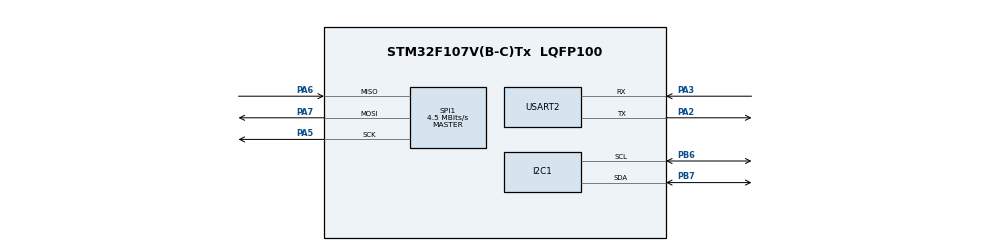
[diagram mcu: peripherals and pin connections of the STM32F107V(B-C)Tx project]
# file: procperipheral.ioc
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Dma.Request0=USART2_TX
Dma.USART2_TX.0.Direction=DMA_MEMORY_TO_PERIPH
Dma.USART2_TX.0.Instance=DMA1_Channel7
Dma.USART2_TX.0.MemDataAlignment=DMA_MDATAALIGN_BYTE
Dma.USART2_TX.0.MemInc=DMA_MINC_ENABLE
Dma.USART2_TX.0.Mode=DMA_NORMAL
Dma.USART2_TX.0.PeriphDataAlignment=DMA_PDATAALIGN_BYTE
Dma.USART2_TX.0.PeriphInc=DMA_PINC_DISABLE
Dma.USART2_TX.0.Priority=DMA_PRIORITY_LOW
Mcu.Family=STM32F1
Mcu.Name=STM32F107V(B-C)Tx
Mcu.Package=LQFP100
NVIC.DMA1_Channel7_IRQn=true\:0\:0\:false\:false\:true\:false\:true\:true
NVIC.PriorityGroup=NVIC_PRIORITYGROUP_4
NVIC.USART2_IRQn=true\:0\:0\:false\:false\:true\:true\:true\:true
OSC_IN.Mode=HSE-External-Oscillator
OSC_IN.Signal=RCC_OSC_IN
OSC_OUT.Mode=HSE-External-Oscillator
OSC_OUT.Signal=RCC_OSC_OUT
PA13.Mode=Serial_Wire
PA13.Signal=SYS_JTMS-SWDIO
PA14.Mode=Serial_Wire
PA14.Signal=SYS_JTCK-SWCLK
PA2.Mode=Asynchronous
PA2.Signal=USART2_TX
PA3.Mode=Asynchronous
PA3.Signal=USART2_RX
PA5.Mode=Full_Duplex_Master
PA5.Signal=SPI1_SCK
PA6.Mode=Full_Duplex_Master
PA6.Signal=SPI1_MISO
PA7.Mode=Full_Duplex_Master
PA7.Signal=SPI1_MOSI
PB6.Mode=I2C
PB6.Signal=I2C1_SCL
PB7.Mode=I2C
PB7.Signal=I2C1_SDA
PC14-OSC32_IN.Mode=LSE-External-Oscillator
PC14-OSC32_IN.Signal=RCC_OSC32_IN
PC15-OSC32_OUT.Mode=LSE-External-Oscillator
PC15-OSC32_OUT.Signal=RCC_OSC32_OUT
ProjectManager.HeapSize=0x200
ProjectManager.StackSize=0x400
ProjectManager.TargetToolchain=STM32CubeIDE
RCC.AHBFreq_Value=72000000
RCC.APB1CLKDivider=RCC_HCLK_DIV2
RCC.APB1Freq_Value=36000000
RCC.APB1TimFreq_Value=72000000
RCC.APB2Freq_Value=72000000
RCC.APB2TimFreq_Value=72000000
RCC.EnbaleCSS=true
RCC.HCLKFreq_Value=72000000
RCC.HSEDivPLL=RCC_HSE_PREDIV_DIV5
RCC.HSE_VALUE=25000000
RCC.PLLMUL=RCC_PLL_MUL9
RCC.PLLSourceVirtual=RCC_PLLSOURCE_HSE
RCC.Prediv1Source=RCC_PREDIV1_SOURCE_PLL2
RCC.Prediv2=RCC_HSE_PREDIV2_DIV5
RCC.SYSCLKFreq_VALUE=72000000
RCC.SYSCLKSource=RCC_SYSCLKSOURCE_PLLCLK
RCC.USBFreq_Value=48000000
SPI1.BaudRatePrescaler=SPI_BAUDRATEPRESCALER_16
SPI1.CalculateBaudRate=4.5 MBits/s
SPI1.Direction=SPI_DIRECTION_2LINES
SPI1.Mode=SPI_MODE_MASTER
SPI1.VirtualType=VM_MASTER
USART2.VirtualMode=VM_ASYNC
board=custom

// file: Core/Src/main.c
/* USER CODE BEGIN Header */
/**
 ******************************************************************************
 * @file           : main.c
 * @brief          : Main program body
 ******************************************************************************
 * @attention
 *
 * Copyright (c) 2023 STMicroelectronics.
 * All rights reserved.
 *
 * This software is licensed under terms that can be found in the LICENSE file
 * in the root directory of this software component.
 * If no LICENSE file comes with this software, it is provided AS-IS.
 *
 ******************************************************************************
 */
/* USER CODE END Header */
#include "main.h"

/* USER CODE BEGIN Includes */
#include <stdio.h>
/* USER CODE END Includes */

I2C_HandleTypeDef hi2c1;

SPI_HandleTypeDef hspi1;

UART_HandleTypeDef huart2;
DMA_HandleTypeDef hdma_usart2_tx;

void SystemClock_Config(void);
static void MX_GPIO_Init(void);
static void MX_I2C1_Init(void);
static void MX_DMA_Init(void);
static void MX_USART2_UART_Init(void);
static void MX_SPI1_Init(void);

/* USER CODE BEGIN 0 */
int __io_putchar(int ch) {
	HAL_UART_Transmit(&huart2, (uint8_t*) &ch, 1, HAL_MAX_DELAY);
	return ch;
}
/* USER CODE END 0 */

int main(void) {

	/* MCU Configuration--------------------------------------------------------*/

	/* Reset of all peripherals, Initializes the Flash interface and the Systick. */
	HAL_Init();

	/* Configure the system clock */
	SystemClock_Config();

	/* Initialize all configured peripherals */
	MX_GPIO_Init();
	MX_I2C1_Init();
	MX_DMA_Init();
	MX_USART2_UART_Init();
	MX_SPI1_Init();

	/* Infinite loop */
	/* USER CODE BEGIN WHILE */
	int ii = 0;
	uint32_t tick;
//	HAL_SetTickFreq(HAL_TICK_FREQ_10HZ);
	CoreDebug->DEMCR |= CoreDebug_DEMCR_TRCENA_Msk;
	DWT->CYCCNT = 0;
	DWT->CTRL |= DWT_CTRL_CYCCNTENA_Msk;

	while (1) {
		/* USER CODE END WHILE */

		/* USER CODE BEGIN 3 */
		tick = HAL_GetTick();
		printf("meet count %06d: %10lu - %10lu/%6ld \n\r", ii++, tick, DWT->CYCCNT, DWT->CYCCNT/tick);
	}
	/* USER CODE END 3 */
}

void SystemClock_Config(void) {
	RCC_OscInitTypeDef RCC_OscInitStruct = { 0 };
	RCC_ClkInitTypeDef RCC_ClkInitStruct = { 0 };

	/** Initializes the RCC Oscillators according to the specified parameters
	 * in the RCC_OscInitTypeDef structure.
	 */
	RCC_OscInitStruct.OscillatorType = RCC_OSCILLATORTYPE_HSE;
	RCC_OscInitStruct.HSEState = RCC_HSE_ON;
	RCC_OscInitStruct.HSEPredivValue = RCC_HSE_PREDIV_DIV5;
	RCC_OscInitStruct.HSIState = RCC_HSI_ON;
	RCC_OscInitStruct.Prediv1Source = RCC_PREDIV1_SOURCE_PLL2;
	RCC_OscInitStruct.PLL.PLLState = RCC_PLL_ON;
	RCC_OscInitStruct.PLL.PLLSource = RCC_PLLSOURCE_HSE;
//	RCC_OscInitStruct.PLL.PLLMUL = RCC_PLL_MUL9;
	RCC_OscInitStruct.PLL.PLLMUL = RCC_PLL_MUL6;
	RCC_OscInitStruct.PLL2.PLL2State = RCC_PLL2_ON;
	RCC_OscInitStruct.PLL2.PLL2MUL = RCC_PLL2_MUL8;
	RCC_OscInitStruct.PLL2.HSEPrediv2Value = RCC_HSE_PREDIV2_DIV5;
	if (HAL_RCC_OscConfig(&RCC_OscInitStruct) != HAL_OK) {
		Error_Handler();
	}

	/** Initializes the CPU, AHB and APB buses clocks
	 */
	RCC_ClkInitStruct.ClockType = RCC_CLOCKTYPE_HCLK | RCC_CLOCKTYPE_SYSCLK
			| RCC_CLOCKTYPE_PCLK1 | RCC_CLOCKTYPE_PCLK2;
	RCC_ClkInitStruct.SYSCLKSource = RCC_SYSCLKSOURCE_PLLCLK;
	RCC_ClkInitStruct.AHBCLKDivider = RCC_SYSCLK_DIV1;
	RCC_ClkInitStruct.APB1CLKDivider = RCC_HCLK_DIV2;
	RCC_ClkInitStruct.APB2CLKDivider = RCC_HCLK_DIV1;

	if (HAL_RCC_ClockConfig(&RCC_ClkInitStruct, FLASH_LATENCY_2) != HAL_OK) {
		Error_Handler();
	}

	/** Enables the Clock Security System
	 */
	HAL_RCC_EnableCSS();

	/** Configure the Systick interrupt time
	 */
	__HAL_RCC_PLLI2S_ENABLE();
}

static void MX_I2C1_Init(void) {

	hi2c1.Instance = I2C1;
	hi2c1.Init.ClockSpeed = 100000;
	hi2c1.Init.DutyCycle = I2C_DUTYCYCLE_2;
	hi2c1.Init.OwnAddress1 = 0;
	hi2c1.Init.AddressingMode = I2C_ADDRESSINGMODE_7BIT;
	hi2c1.Init.DualAddressMode = I2C_DUALADDRESS_DISABLE;
	hi2c1.Init.OwnAddress2 = 0;
	hi2c1.Init.GeneralCallMode = I2C_GENERALCALL_DISABLE;
	hi2c1.Init.NoStretchMode = I2C_NOSTRETCH_DISABLE;
	if (HAL_I2C_Init(&hi2c1) != HAL_OK) {
		Error_Handler();
	}

}

static void MX_SPI1_Init(void) {

	/* SPI1 parameter configuration*/
	hspi1.Instance = SPI1;
	hspi1.Init.Mode = SPI_MODE_MASTER;
	hspi1.Init.Direction = SPI_DIRECTION_2LINES;
	hspi1.Init.DataSize = SPI_DATASIZE_8BIT;
	hspi1.Init.CLKPolarity = SPI_POLARITY_LOW;
	hspi1.Init.CLKPhase = SPI_PHASE_1EDGE;
	hspi1.Init.NSS = SPI_NSS_SOFT;
	hspi1.Init.BaudRatePrescaler = SPI_BAUDRATEPRESCALER_16;
	hspi1.Init.FirstBit = SPI_FIRSTBIT_MSB;
	hspi1.Init.TIMode = SPI_TIMODE_DISABLE;
	hspi1.Init.CRCCalculation = SPI_CRCCALCULATION_DISABLE;
	hspi1.Init.CRCPolynomial = 10;
	if (HAL_SPI_Init(&hspi1) != HAL_OK) {
		Error_Handler();
	}

}

static void MX_USART2_UART_Init(void) {

	huart2.Instance = USART2;
	huart2.Init.BaudRate = 115200;
	huart2.Init.WordLength = UART_WORDLENGTH_8B;
	huart2.Init.StopBits = UART_STOPBITS_1;
	huart2.Init.Parity = UART_PARITY_NONE;
	huart2.Init.Mode = UART_MODE_TX_RX;
	huart2.Init.HwFlowCtl = UART_HWCONTROL_NONE;
	huart2.Init.OverSampling = UART_OVERSAMPLING_16;
	if (HAL_UART_Init(&huart2) != HAL_OK) {
		Error_Handler();
	}

}

static void MX_DMA_Init(void) {

	/* DMA controller clock enable */
	__HAL_RCC_DMA1_CLK_ENABLE();

	/* DMA interrupt init */
	/* DMA1_Channel7_IRQn interrupt configuration */
	HAL_NVIC_SetPriority(DMA1_Channel7_IRQn, 0, 0);
	HAL_NVIC_EnableIRQ(DMA1_Channel7_IRQn);

}

static void MX_GPIO_Init(void) {

	/* GPIO Ports Clock Enable */
	__HAL_RCC_GPIOC_CLK_ENABLE();
	__HAL_RCC_GPIOA_CLK_ENABLE();
	__HAL_RCC_GPIOB_CLK_ENABLE();

}

void Error_Handler(void) {
	__disable_irq();
	while (1) {
	}
}
